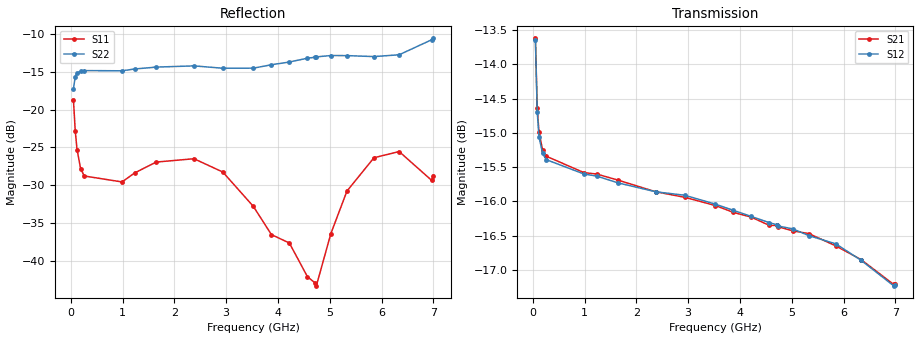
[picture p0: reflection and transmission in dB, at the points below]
! Integrated Device Technology
! Corporate Headquarters
! 6024 Silver Creek Valley Road
! San Jose, CA 95138  USA
! Phone:  1-408-284-8200
! Toll Free:  1-800-223-1366
! Webpage:  http://www.idt.com/
! Timing and RF Division
! 515 Groton Road, Suite 102
! Westford, MA 01886-6024
! Device:  F2258
! Description: Voltage Variable RF Attenuator
! Frequency:  50.0 -  6000.00 MHz
! Package:  3x3 mm Thin QFN Plastic Package: 16 pin
! Ports:  2 RF, 2 DC
!  Pin  1  = NC
!  Pin  2  = NC
!  Pin  3  = RF2  = Port 2
!  Pin  4  = GND
!  Pin  5  = Vdd
!  Pin  6  = NC
!  Pin  7  = VCTRL
!  Pin  8  = NC
!  Pin  9  = GND
!  Pin 10  = RF1  = Port 1
!  Pin 11  = NC
!  Pin 12  = NC
!  Pin 13  = NC
!  Pin 14  = NC
!  Pin 15  = NC
!  Pin 16  = NC
! Vcntrl:  1.190 Volts
! Vdd:  +3.300 Volts
! Current:  1.164 mA
! Data:  The device was measured on a the F2258 evaluation board which has
!  individual transmission lines to the RF pins.  Data was collected
!  using a calibrated network analyzer.  The evaluation board was
!  de-embedded using a TRL calibration technique.
!  The reference plane is the edge of the package pin.
! Misc:  SN 10
!  Action Tracker AT0285
! Date Measured:  2014-12-10
! Date:  2016-01-13  MJV
! Note:
!  Integrated Device Technology supplies this data as a sample of measured
!  data at the package pin for this product.  Your particular data for this
!  product may vary.
!  Data was taken at 25 degrees C.
!  Integrated Device Technology reserves the right to change this data at anytime.
!Freq_(GHz)  S11M_(dB)  S11P_(deg)  S21M_(dB)  S21P_(deg)  S12M_(dB)  S12P_(deg)  S22M_(dB)  S22P_(deg)
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# GHz S dB R 50
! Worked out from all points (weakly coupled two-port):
!   201 points, 50 MHz to 7 GHz, reference 50 ohm
!   highest |S21| = -13.62 dB at 50 MHz (marker M1); lowest = -17.2 dB at 6.965 GHz (marker M2)
!   lowest |S11| = -43.3 dB at 4.741 GHz (marker M3), VSWR 1.01, Z = 50.5 + j0.419 ohm
!   |S11| at or under -10 dB: start of sweep to end of sweep
!   |S22| runs from -17.3 to -10.6 dB; largest |S21 - S12| = 0.0015
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0.05  -18.71 -93.4  -13.62 -23.1  -13.64 -23.2  -17.28 -22.2
0.08475  -22.84 -78.5  -14.64 -16.5  -14.69 -16.6  -15.67 -11.8
0.1195  -25.30 -66.4  -14.99 -13.2  -15.06 -13.3  -15.21 -9.7
0.189  -27.82 -49.9  -15.25 -10.5  -15.30 -10.5  -14.96 -9.1
0.2585  -28.79 -38.3  -15.34 -9.7  -15.39 -9.7  -14.85 -9.9
0.98825  -29.58 -19.0  -15.58 -16.9  -15.60 -16.9  -14.88 -28.3
1.2315  -28.39 -15.0  -15.60 -20.3  -15.63 -20.3  -14.64 -34.3
1.6485  -26.95 -10.7  -15.69 -26.2  -15.73 -26.2  -14.39 -44.2
2.37825  -26.51 0.7  -15.86 -36.6  -15.86 -36.6  -14.23 -61.4
2.93425  -28.27 13.6  -15.94 -44.7  -15.91 -44.8  -14.54 -77.4
3.525  -32.82 37.3  -16.06 -53.5  -16.04 -53.5  -14.53 -99.2
3.8725  -36.54 64.2  -16.16 -58.6  -16.13 -58.7  -14.08 -112.0
4.22  -37.66 84.8  -16.23 -63.8  -16.22 -63.8  -13.72 -122.2
4.5675  -42.10 76.6  -16.35 -68.8  -16.31 -68.8  -13.21 -130.2
4.7065  -42.89 43.3  -16.35 -70.7  -16.34 -70.7  -13.10 -132.5
4.74125  -43.30 37.3  -16.37 -71.3  -16.36 -71.3  -13.04 -133.0
5.01925  -36.44 -5.0  -16.43 -75.2  -16.40 -75.2  -12.86 -137.2
5.332  -30.78 -12.3  -16.47 -79.7  -16.50 -79.6  -12.87 -141.0
5.85325  -26.38 -5.2  -16.65 -86.9  -16.62 -87.0  -13.00 -150.2
6.33975  -25.56 8.4  -16.85 -93.8  -16.86 -93.8  -12.76 -162.3
6.96525  -29.36 80.3  -17.21 -101.7  -17.23 -101.6  -10.78 179.7
7  -28.82 88.6  -17.20 -102.0  -17.22 -102.0  -10.59 178.6
